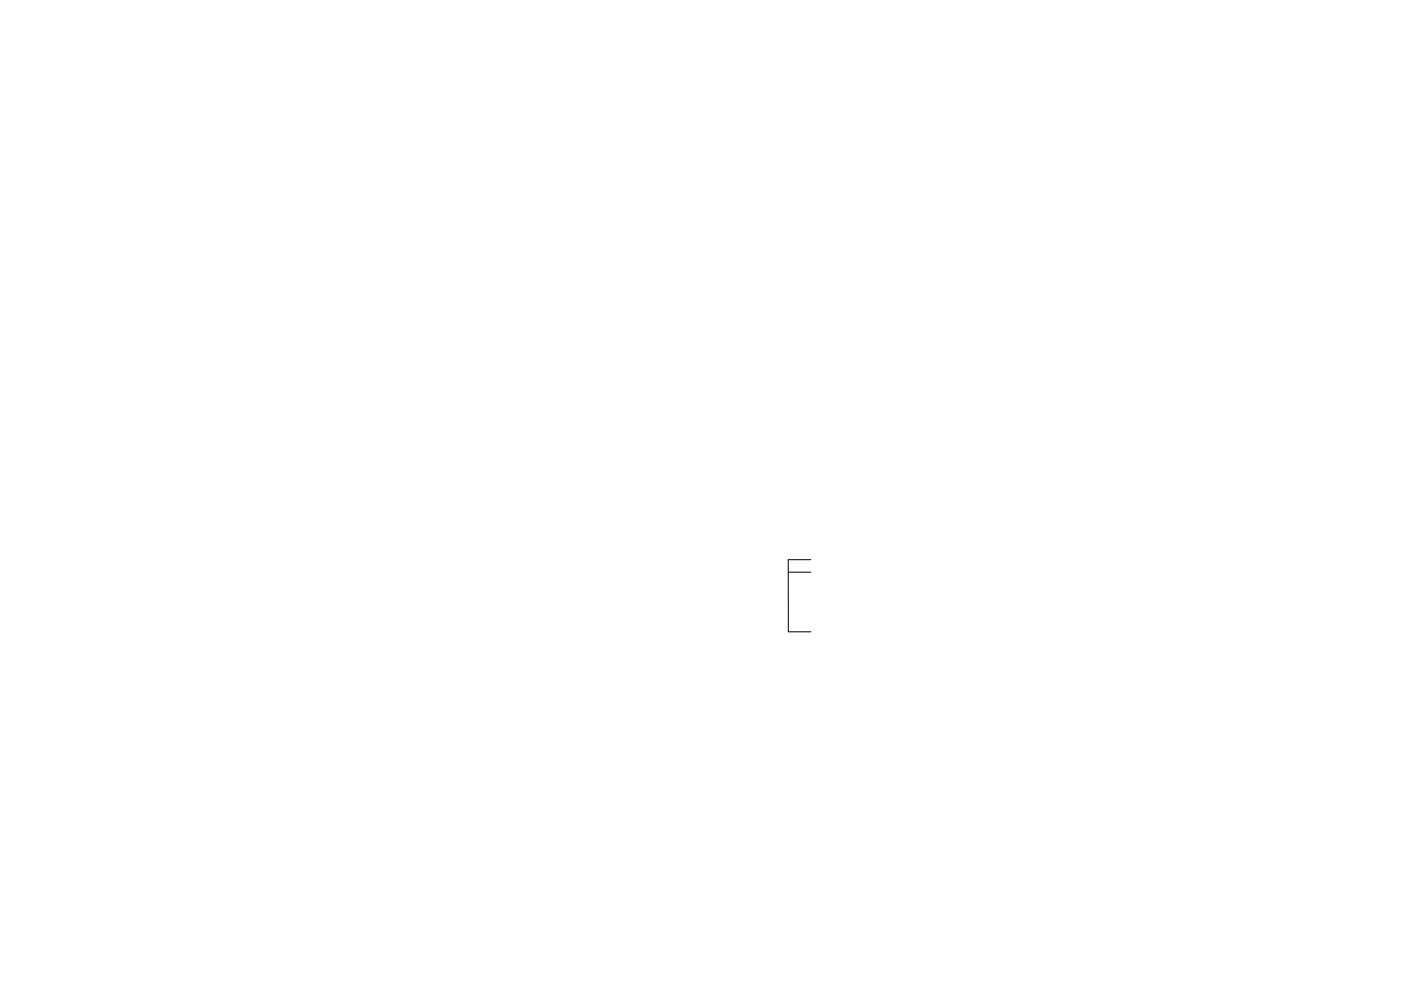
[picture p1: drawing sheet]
<svg xmlns="http://www.w3.org/2000/svg" width="297mm" height="210mm" viewBox="0 0 297 210" stroke-linecap="round" stroke-linejoin="round" font-family="sans-serif">
<path d="M171.9 118.7h-4.8v15.3h4.8M167.1 121.4h4.8" fill="none" stroke="#000" stroke-width=".21"/>
<g fill="#fff" stroke="#fff" stroke-width=".21">
<circle cx="119" cy="145.2" r=".17"/>
<circle cx="131" cy="145.2" r=".17"/>
<circle cx="92" cy="145.2" r=".17"/>
<circle cx="71" cy="145.2" r=".17"/>
<circle cx="182.9" cy="109.5" r=".17"/>
<circle cx="54.5" cy="119.9" r=".17"/>
<circle cx="54.5" cy="141.5" r=".17"/>
<circle cx="41.8" cy="114.3" r=".17"/>
<circle cx="135.7" cy="125.5" r=".17"/>
<circle cx="175.6" cy="120.4" r=".17"/>
<circle cx="140.3" cy="118.1" r=".17"/>
<circle cx="173.8" cy="130.2" r=".17"/>
<circle cx="134.2" cy="116.1" r=".17"/>
<circle cx="92.9" cy="119.1" r=".17"/>
<circle cx="181" cy="125.2" r=".18"/>
<circle cx="168.5" cy="132.8" r=".17"/>
<circle cx="168.5" cy="130.3" r=".17"/>
<circle cx="168.5" cy="127.7" r=".17"/>
<circle cx="168.5" cy="125.2" r=".17"/>
<circle cx="168.5" cy="122.7" r=".17"/>
<circle cx="168.5" cy="120.1" r=".17"/>
<circle cx="41" cy="125.2" r=".17"/>
<circle cx="114" cy="110.2" r=".17"/>
</g>
<path d="M106.7 106.5v1.3M106.7 110.4v1M107.9 110.2h.2M115.3 106.5v1.3M115.3 110.5v1" fill="none" stroke="#fff" stroke-width=".6"/>
</svg>
